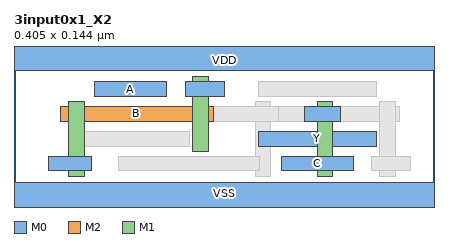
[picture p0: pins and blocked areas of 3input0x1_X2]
MACRO 3input0x1_X2
  CLASS CORE ;
  ORIGIN 0 0 ;
  FOREIGN 3input0x1_X2 0 0 ;
  SIZE 0.4050 BY 0.1440 ;
  SYMMETRY X Y ;
  SITE coresite ;
  PIN A
    DIRECTION INPUT ;
    USE SIGNAL ;
    PORT
      LAYER M0 ;
        RECT 0.0780 0.1010 0.1470 0.1150 ;
    END
  END A
  PIN B
    DIRECTION INPUT ;
    USE SIGNAL ;
    PORT
      LAYER M2 ;
        RECT 0.0450 0.0770 0.1920 0.0910 ;
      LAYER M1 ;
        RECT 0.0525 0.0240 0.0675 0.0960 ;
        RECT 0.1725 0.0480 0.1875 0.1200 ;
      LAYER M0 ;
        RECT 0.1650 0.1010 0.2025 0.1150 ;
        RECT 0.0330 0.0290 0.0750 0.0430 ;
    END
  END B
  PIN C
    DIRECTION INPUT ;
    USE SIGNAL ;
    PORT
      LAYER M0 ;
        RECT 0.2580 0.0290 0.3270 0.0430 ;
    END
  END C
  PIN Y
    DIRECTION OUTPUT ;
    USE SIGNAL ;
    PORT
      LAYER M1 ;
        RECT 0.2925 0.0240 0.3075 0.0960 ;
      LAYER M0 ;
        RECT 0.2805 0.0770 0.3150 0.0910 ;
        RECT 0.2355 0.0530 0.3495 0.0670 ;
    END
  END Y
  PIN VDD
    DIRECTION INOUT ;
    USE POWER ;
    SHAPE ABUTMENT ;
    PORT
      LAYER M0 ;
        RECT 0.0000 0.1260 0.4050 0.1620 ;
    END
  END VDD
  PIN VSS
    DIRECTION INOUT ;
    USE GROUND ;
    SHAPE ABUTMENT ;
    PORT
      LAYER M0 ;
        RECT 0.0000 -0.0180 0.4050 0.0180 ;
    END
  END VSS
  OBS
    LAYER M2 ;
      RECT 0.2250 0.0770 0.3720 0.0910 ;
    LAYER V1 ;
      RECT 0.0530 0.0770 0.0670 0.0910 ;
      RECT 0.1730 0.0770 0.1870 0.0910 ;
      RECT 0.2330 0.0770 0.2470 0.0910 ;
      RECT 0.3530 0.0770 0.3670 0.0910 ;
    LAYER M1 ;
      RECT 0.2325 0.0240 0.2475 0.0960 ;
      RECT 0.3525 0.0240 0.3675 0.0960 ;
    LAYER V0 ;
      RECT 0.0530 0.0290 0.0670 0.0430 ;
      RECT 0.1730 0.1010 0.1870 0.1150 ;
      RECT 0.2330 0.0770 0.2470 0.0910 ;
      RECT 0.3530 0.0290 0.3670 0.0430 ;
      RECT 0.2930 0.0770 0.3070 0.0910 ;
      RECT 0.2930 0.0530 0.3070 0.0670 ;
    LAYER M0 ;
      RECT 0.1005 0.0290 0.2370 0.0430 ;
      RECT 0.3450 0.0290 0.3825 0.0430 ;
      RECT 0.0555 0.0530 0.1695 0.0670 ;
      RECT 0.0555 0.0770 0.2550 0.0910 ;
      RECT 0.2355 0.1010 0.3495 0.1150 ;
  END
END 3input0x1_X2
